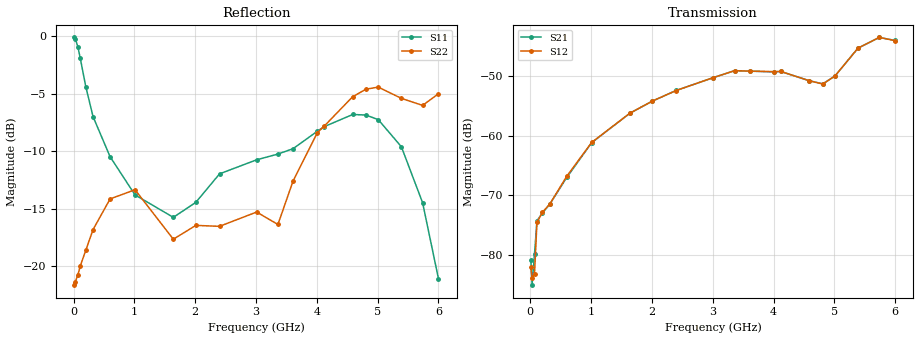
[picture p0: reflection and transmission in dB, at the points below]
!Agilent Technologies,N5230A,MY45001650,A.07.50.48
!Agilent N5230A: A.07.50.48
!Date: Saturday, July 08, 2017 15:54:41
!Correction: S11(Full 2 Port(1,2))
!S21(Full 2 Port(1,2))
!S12(Full 2 Port(1,2))
!S22(Full 2 Port(1,2))
!S2P File: Measurements: S11, S21, S12, S22:
# Hz S  dB  R 50
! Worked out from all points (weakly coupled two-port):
!   600 points, 10 MHz to 6 GHz, reference 50 ohm
!   highest |S21| = -43.60 dB at 5.74 GHz (marker M1); lowest = -85.0 dB at 30 MHz (marker M2)
!   lowest |S11| = -21.1 dB at 6 GHz (marker M3), VSWR 1.19, Z = 59.6 + j1.17 ohm
!   |S11| at or under -10 dB: 547.9 MHz to 3.538 GHz (2.99 GHz wide, 146 % of centre); 5.439 GHz to end of sweep
!   |S22| runs from -21.6 to -4.4 dB; largest |S21 - S12| = 0.00013
!   S11 on the Smith chart (normalised r, x): 10 MHz: 2, -19; 110 MHz: 0.50, -1.81; 320 MHz: 0.52, -0.54; 2.4 GHz: 0.61, +0.09; 4.12 GHz: 1.67, +0.92; 6 GHz: 1.19, +0.02
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1e7  -0.12 -6.0  -80.76 -53.4  -82.03 45.1  -21.65 -6.4
3e7  -0.27 -17.1  -85.00 53.7  -83.82 43.3  -21.34 -10.3
7e7  -0.93 -37.7  -79.79 99.0  -83.11 75.5  -20.77 -23.9
1.1e8  -1.94 -55.1  -74.23 62.2  -74.53 42.1  -19.99 -35.0
2e8  -4.39 -84.6  -72.97 47.7  -72.82 47.3  -18.63 -57.9
3.2e8  -7.01 -112.0  -71.49 43.3  -71.47 45.5  -16.82 -81.4
6e8  -10.49 -152.0  -67.01 45.5  -66.80 46.0  -14.16 -117.1
1.01e9  -13.81 178.4  -61.19 27.3  -61.15 27.0  -13.36 -153.7
1.64e9  -15.76 171.5  -56.26 -17.7  -56.25 -17.7  -17.66 168.8
2.01e9  -14.46 174.7  -54.23 -45.0  -54.23 -44.7  -16.46 159.6
2.4e9  -11.98 163.8  -52.46 -76.9  -52.47 -76.8  -16.54 136.3
3.01e9  -10.76 131.1  -50.32 -127.5  -50.31 -127.4  -15.30 132.6
3.36e9  -10.26 101.7  -49.15 -164.4  -49.16 -164.5  -16.38 149.8
3.61e9  -9.79 78.5  -49.24 169.4  -49.23 169.5  -12.59 169.0
4.01e9  -8.27 42.6  -49.35 134.2  -49.32 134.1  -8.39 157.7
4.12e9  -7.88 35.1  -49.29 124.2  -49.28 124.1  -7.84 155.1
4.59e9  -6.82 10.0  -50.84 86.5  -50.84 86.6  -5.27 134.0
4.81e9  -6.87 1.1  -51.35 81.4  -51.39 81.5  -4.62 118.1
5.01e9  -7.27 -5.8  -50.06 79.1  -50.05 79.4  -4.44 103.5
5.39e9  -9.62 -17.7  -45.38 52.5  -45.39 52.6  -5.42 77.6
5.74e9  -14.50 -21.7  -43.60 7.0  -43.59 7.1  -6.03 69.5
6e9  -21.09 6.3  -44.10 -17.5  -44.14 -17.2  -5.02 56.3
